VERSION 5.4 ;
NAMESCASESENSITIVE ON ;
BUSBITCHARS "[]" ;
DIVIDERCHAR "/" ;
UNITS
  DATABASE MICRONS 2000 ;
END UNITS
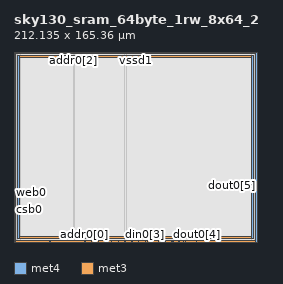
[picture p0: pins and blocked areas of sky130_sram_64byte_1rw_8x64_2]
MACRO sky130_sram_64byte_1rw_8x64_2
   CLASS BLOCK ;
   SIZE 212.135 BY 165.36 ;
   SYMMETRY X Y R90 ;
   PIN din0[0]
      DIRECTION INPUT ;
      PORT
         LAYER met4 ;
         RECT  96.56 0.0 96.94 0.38 ;
      END
   END din0[0]
   PIN din0[1]
      DIRECTION INPUT ;
      PORT
         LAYER met4 ;
         RECT  102.4 0.0 102.78 0.38 ;
      END
   END din0[1]
   PIN din0[2]
      DIRECTION INPUT ;
      PORT
         LAYER met4 ;
         RECT  108.24 0.0 108.62 0.38 ;
      END
   END din0[2]
   PIN din0[3]
      DIRECTION INPUT ;
      PORT
         LAYER met4 ;
         RECT  114.08 0.0 114.46 0.38 ;
      END
   END din0[3]
   PIN din0[4]
      DIRECTION INPUT ;
      PORT
         LAYER met4 ;
         RECT  119.92 0.0 120.3 0.38 ;
      END
   END din0[4]
   PIN din0[5]
      DIRECTION INPUT ;
      PORT
         LAYER met4 ;
         RECT  125.76 0.0 126.14 0.38 ;
      END
   END din0[5]
   PIN din0[6]
      DIRECTION INPUT ;
      PORT
         LAYER met4 ;
         RECT  131.6 0.0 131.98 0.38 ;
      END
   END din0[6]
   PIN din0[7]
      DIRECTION INPUT ;
      PORT
         LAYER met4 ;
         RECT  137.44 0.0 137.82 0.38 ;
      END
   END din0[7]
   PIN din0[8]
      DIRECTION INPUT ;
      PORT
         LAYER met4 ;
         RECT  143.28 0.0 143.66 0.38 ;
      END
   END din0[8]
   PIN addr0[0]
      DIRECTION INPUT ;
      PORT
         LAYER met4 ;
         RECT  61.52 0.0 61.9 0.38 ;
      END
   END addr0[0]
   PIN addr0[1]
      DIRECTION INPUT ;
      PORT
         LAYER met4 ;
         RECT  67.36 0.0 67.74 0.38 ;
      END
   END addr0[1]
   PIN addr0[2]
      DIRECTION INPUT ;
      PORT
         LAYER met4 ;
         RECT  51.965 164.98 52.345 165.36 ;
      END
   END addr0[2]
   PIN addr0[3]
      DIRECTION INPUT ;
      PORT
         LAYER met4 ;
         RECT  48.3 164.98 48.68 165.36 ;
      END
   END addr0[3]
   PIN addr0[4]
      DIRECTION INPUT ;
      PORT
         LAYER met4 ;
         RECT  51.275 164.98 51.655 165.36 ;
      END
   END addr0[4]
   PIN addr0[5]
      DIRECTION INPUT ;
      PORT
         LAYER met4 ;
         RECT  50.585 164.98 50.965 165.36 ;
      END
   END addr0[5]
   PIN addr0[6]
      DIRECTION INPUT ;
      PORT
         LAYER met4 ;
         RECT  49.84 164.98 50.22 165.36 ;
      END
   END addr0[6]
   PIN csb0
      DIRECTION INPUT ;
      PORT
         LAYER met3 ;
         RECT  0.0 27.69 0.38 28.07 ;
      END
   END csb0
   PIN web0
      DIRECTION INPUT ;
      PORT
         LAYER met3 ;
         RECT  0.0 36.19 0.38 36.57 ;
      END
   END web0
   PIN clk0
      DIRECTION INPUT ;
      PORT
         LAYER met4 ;
         RECT  31.1 0.0 31.48 0.38 ;
      END
   END clk0
   PIN wmask0[0]
      DIRECTION INPUT ;
      PORT
         LAYER met4 ;
         RECT  73.2 0.0 73.58 0.38 ;
      END
   END wmask0[0]
   PIN wmask0[1]
      DIRECTION INPUT ;
      PORT
         LAYER met4 ;
         RECT  79.04 0.0 79.42 0.38 ;
      END
   END wmask0[1]
   PIN wmask0[2]
      DIRECTION INPUT ;
      PORT
         LAYER met4 ;
         RECT  84.88 0.0 85.26 0.38 ;
      END
   END wmask0[2]
   PIN wmask0[3]
      DIRECTION INPUT ;
      PORT
         LAYER met4 ;
         RECT  90.72 0.0 91.1 0.38 ;
      END
   END wmask0[3]
   PIN spare_wen0
      DIRECTION INPUT ;
      PORT
         LAYER met4 ;
         RECT  149.12 0.0 149.5 0.38 ;
      END
   END spare_wen0
   PIN dout0[0]
      DIRECTION OUTPUT ;
      PORT
         LAYER met4 ;
         RECT  116.095 0.0 116.475 0.38 ;
      END
   END dout0[0]
   PIN dout0[1]
      DIRECTION OUTPUT ;
      PORT
         LAYER met4 ;
         RECT  127.36 0.0 127.74 0.38 ;
      END
   END dout0[1]
   PIN dout0[2]
      DIRECTION OUTPUT ;
      PORT
         LAYER met4 ;
         RECT  138.74 0.0 139.12 0.38 ;
      END
   END dout0[2]
   PIN dout0[3]
      DIRECTION OUTPUT ;
      PORT
         LAYER met4 ;
         RECT  147.315 0.0 147.695 0.38 ;
      END
   END dout0[3]
   PIN dout0[4]
      DIRECTION OUTPUT ;
      PORT
         LAYER met4 ;
         RECT  158.74 0.0 159.12 0.38 ;
      END
   END dout0[4]
   PIN dout0[5]
      DIRECTION OUTPUT ;
      PORT
         LAYER met3 ;
         RECT  211.755 49.405 212.135 49.785 ;
      END
   END dout0[5]
   PIN dout0[6]
      DIRECTION OUTPUT ;
      PORT
         LAYER met3 ;
         RECT  211.755 50.095 212.135 50.475 ;
      END
   END dout0[6]
   PIN dout0[7]
      DIRECTION OUTPUT ;
      PORT
         LAYER met3 ;
         RECT  211.755 52.275 212.135 52.655 ;
      END
   END dout0[7]
   PIN dout0[8]
      DIRECTION OUTPUT ;
      PORT
         LAYER met3 ;
         RECT  211.755 50.785 212.135 51.165 ;
      END
   END dout0[8]
   PIN vccd1
      DIRECTION INOUT ;
      USE POWER ; 
      SHAPE ABUTMENT ; 
      PORT
         LAYER met4 ;
         RECT  210.395 0.0 212.135 165.36 ;
         LAYER met4 ;
         RECT  0.0 0.0 1.74 165.36 ;
         LAYER met3 ;
         RECT  0.0 163.62 212.135 165.36 ;
         LAYER met3 ;
         RECT  0.0 0.0 212.135 1.74 ;
      END
   END vccd1
   PIN vssd1
      DIRECTION INOUT ;
      USE GROUND ; 
      SHAPE ABUTMENT ; 
      PORT
         LAYER met3 ;
         RECT  3.48 160.14 208.655 161.88 ;
         LAYER met3 ;
         RECT  3.48 3.48 208.655 5.22 ;
         LAYER met4 ;
         RECT  3.48 3.48 5.22 161.88 ;
         LAYER met4 ;
         RECT  206.915 3.48 208.655 161.88 ;
      END
   END vssd1
   OBS
   LAYER  met1 ;
      RECT  0.62 0.62 211.515 164.74 ;
   LAYER  met2 ;
      RECT  0.62 0.62 211.515 164.74 ;
   LAYER  met3 ;
      RECT  0.98 27.09 211.515 28.67 ;
      RECT  0.62 28.67 0.98 35.59 ;
      RECT  0.98 28.67 211.155 48.805 ;
      RECT  0.98 48.805 211.155 50.385 ;
      RECT  211.155 28.67 211.515 48.805 ;
      RECT  0.62 37.17 0.98 163.02 ;
      RECT  211.155 53.255 211.515 163.02 ;
      RECT  0.62 2.34 0.98 27.09 ;
      RECT  0.98 50.385 2.88 159.54 ;
      RECT  0.98 159.54 2.88 162.48 ;
      RECT  0.98 162.48 2.88 163.02 ;
      RECT  2.88 50.385 209.255 159.54 ;
      RECT  2.88 162.48 209.255 163.02 ;
      RECT  209.255 50.385 211.155 159.54 ;
      RECT  209.255 159.54 211.155 162.48 ;
      RECT  209.255 162.48 211.155 163.02 ;
      RECT  0.98 2.34 2.88 2.88 ;
      RECT  0.98 2.88 2.88 5.82 ;
      RECT  0.98 5.82 2.88 27.09 ;
      RECT  2.88 2.34 209.255 2.88 ;
      RECT  2.88 5.82 209.255 27.09 ;
      RECT  209.255 2.34 211.515 2.88 ;
      RECT  209.255 2.88 211.515 5.82 ;
      RECT  209.255 5.82 211.515 27.09 ;
   LAYER  met4 ;
      RECT  95.96 0.98 97.54 164.74 ;
      RECT  97.54 0.62 101.8 0.98 ;
      RECT  103.38 0.62 107.64 0.98 ;
      RECT  109.22 0.62 113.48 0.98 ;
      RECT  120.9 0.62 125.16 0.98 ;
      RECT  132.58 0.62 136.84 0.98 ;
      RECT  62.5 0.62 66.76 0.98 ;
      RECT  51.365 0.98 52.945 164.38 ;
      RECT  52.945 0.98 95.96 164.38 ;
      RECT  52.945 164.38 95.96 164.74 ;
      RECT  32.08 0.62 60.92 0.98 ;
      RECT  68.34 0.62 72.6 0.98 ;
      RECT  74.18 0.62 78.44 0.98 ;
      RECT  80.02 0.62 84.28 0.98 ;
      RECT  85.86 0.62 90.12 0.98 ;
      RECT  91.7 0.62 95.96 0.98 ;
      RECT  115.06 0.62 115.495 0.98 ;
      RECT  117.075 0.62 119.32 0.98 ;
      RECT  126.74 0.62 126.76 0.98 ;
      RECT  128.34 0.62 131.0 0.98 ;
      RECT  139.72 0.62 142.68 0.98 ;
      RECT  144.26 0.62 146.715 0.98 ;
      RECT  148.295 0.62 148.52 0.98 ;
      RECT  150.1 0.62 158.14 0.98 ;
      RECT  159.72 0.62 209.795 0.98 ;
      RECT  2.34 164.38 47.7 164.74 ;
      RECT  2.34 0.62 30.5 0.98 ;
      RECT  2.34 0.98 2.88 2.88 ;
      RECT  2.34 2.88 2.88 162.48 ;
      RECT  2.34 162.48 2.88 164.38 ;
      RECT  2.88 0.98 5.82 2.88 ;
      RECT  2.88 162.48 5.82 164.38 ;
      RECT  5.82 0.98 51.365 2.88 ;
      RECT  5.82 2.88 51.365 162.48 ;
      RECT  5.82 162.48 51.365 164.38 ;
      RECT  97.54 0.98 206.315 2.88 ;
      RECT  97.54 2.88 206.315 162.48 ;
      RECT  97.54 162.48 206.315 164.74 ;
      RECT  206.315 0.98 209.255 2.88 ;
      RECT  206.315 162.48 209.255 164.74 ;
      RECT  209.255 0.98 209.795 2.88 ;
      RECT  209.255 2.88 209.795 162.48 ;
      RECT  209.255 162.48 209.795 164.74 ;
   END
END    sky130_sram_64byte_1rw_8x64_2
END    LIBRARY
